VERSION 5.8 ;
BUSBITCHARS "[]" ;
DIVIDERCHAR "/" ;
CLEARANCEMEASURE EUCLIDEAN ;

SITE coresite_DH_P
    SIZE 0.0450 BY 0.2880 ;
    CLASS CORE ;
    SYMMETRY X Y ;
END coresite_DH_P

SITE coresite_DH_N
    SIZE 0.0450 BY 0.2880 ;
    CLASS CORE ;
    SYMMETRY X Y ;
END coresite_DH_N

SITE coresite
    SIZE 0.0450 BY 0.1440 ;
    CLASS CORE ;
    SYMMETRY X Y ;
END coresite

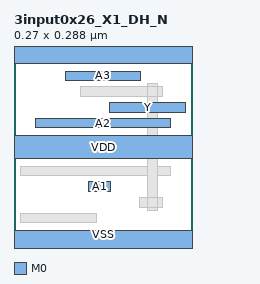
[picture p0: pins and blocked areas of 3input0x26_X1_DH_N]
MACRO 3input0x26_X1_DH_N
  CLASS CORE ;
  ORIGIN 0 0 ;
  FOREIGN 3input0x26_X1_DH_N 0 0 ;
  SIZE 0.2700 BY 0.2880 ;
  SYMMETRY X Y ;
  SITE coresite_DH_N ;
  PIN A1
    DIRECTION INPUT ;
    USE SIGNAL ;
    PORT
      LAYER M0 ;
        RECT 0.1125 0.0910 0.1470 0.0770 ;
    END
  END A1
  PIN A2
    DIRECTION INPUT ;
    USE SIGNAL ;
    PORT
      LAYER M0 ;
        RECT 0.0330 0.1870 0.2370 0.1730 ;
    END
  END A2
  PIN Y
    DIRECTION OUTPUT ;
    USE SIGNAL ;
    PORT
      LAYER M0 ;
        RECT 0.1455 0.2110 0.2595 0.1970 ;
    END
  END Y
  PIN A3
    DIRECTION INPUT ;
    USE SIGNAL ;
    PORT
      LAYER M0 ;
        RECT 0.0780 0.2590 0.1920 0.2450 ;
    END
  END A3
  PIN VDD
    DIRECTION INOUT ;
    USE POWER ;
    SHAPE ABUTMENT ;
    PORT
      LAYER M0 ;
        RECT 0.0000 0.1260 0.2700 0.1620 ;
    END
  END VDD
  PIN VSS
    DIRECTION INOUT ;
    USE GROUND ;
    SHAPE ABUTMENT ;
    PORT
      LAYER M0 ;
        RECT 0.0000 -0.0180 0.2700 0.0180 ;
        RECT 0.0000 0.2700 0.2700 0.3060 ;
    END
  END VSS
  OBS
      LAYER M0 ;
        RECT 0.0105 0.0290 0.1245 0.0430 ;
        RECT 0.1905 0.0530 0.2250 0.0670 ;
        RECT 0.0105 0.1010 0.2370 0.1150 ;
        RECT 0.1005 0.2210 0.2250 0.2350 ;
      LAYER M1 ;
        RECT 0.2025 0.2400 0.2175 0.0480 ;
      LAYER V0 ;
        RECT 0.2030 0.0530 0.2170 0.0670 ;
        RECT 0.2030 0.2210 0.2170 0.2350 ;
  END
END 3input0x26_X1_DH_N

END LIBRARY
